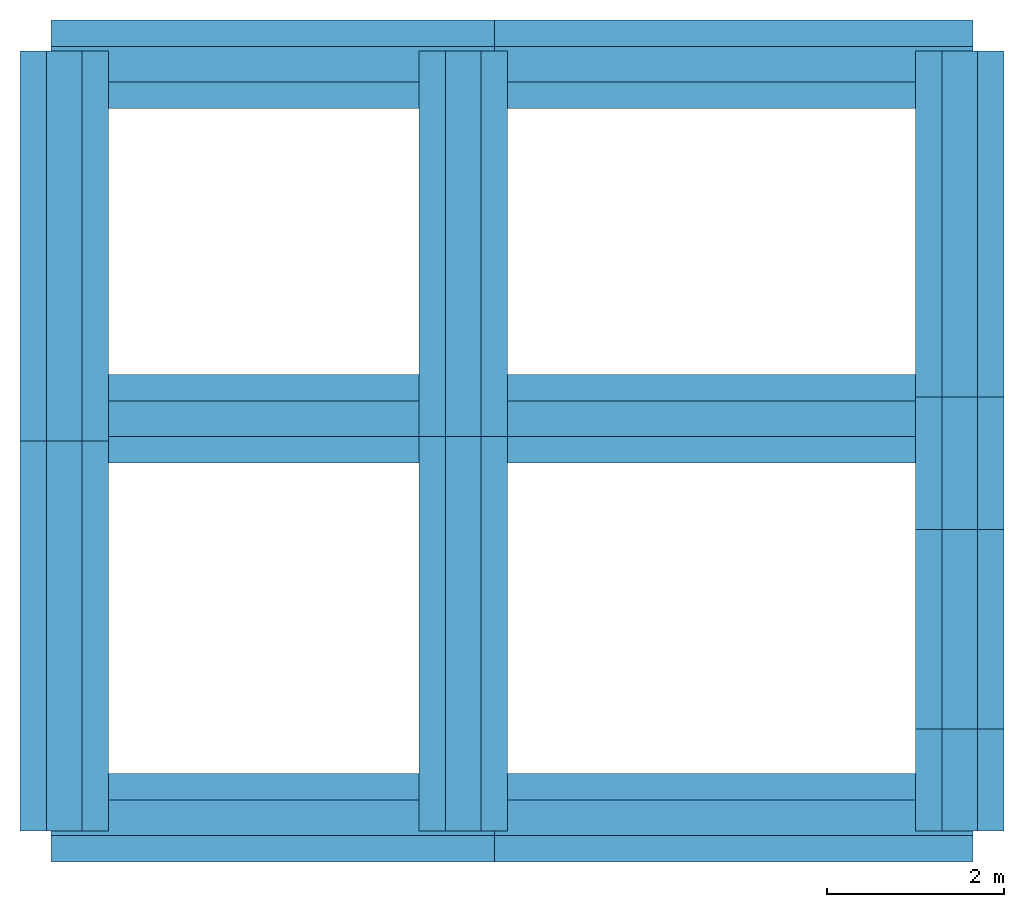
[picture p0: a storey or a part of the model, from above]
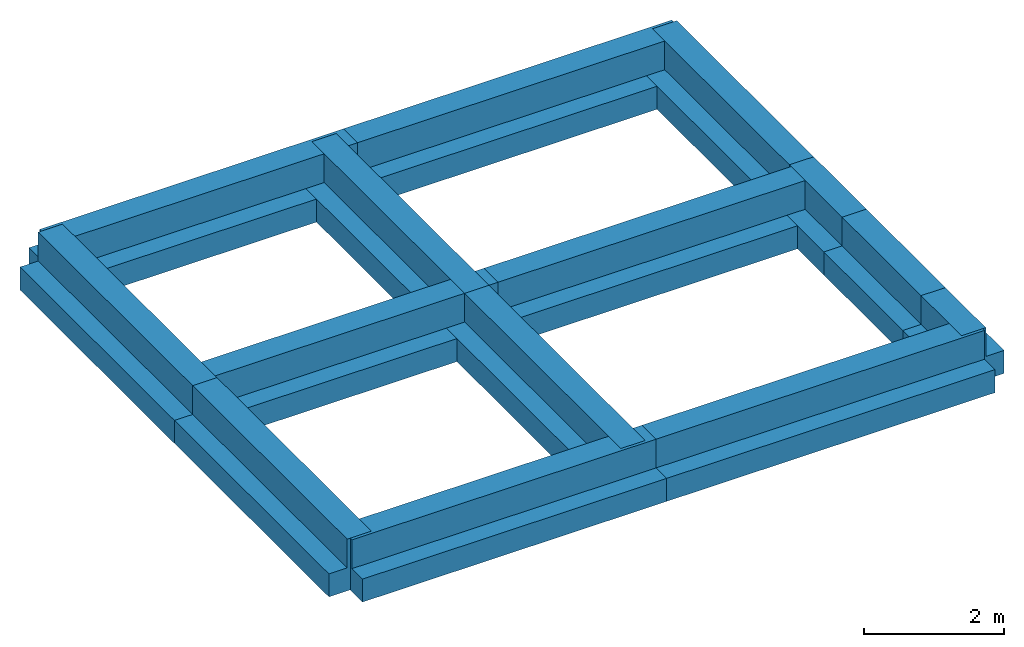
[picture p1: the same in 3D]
Properties of the parts of a building model (IFC2X3)

# File

# IfcSite, Default Site
RefElevation: 0 m

# IfcBuildingStorey (4)
In: Default Building
Name | Elevation (m)
Piano 2 | 6.4
Piano 1 | 3.2
Piano 3 | 1.3
Piano 0 | 0

# IfcBeam (57)
Material: C25/30
Name (Trave:...) | In
1 [Piano:0] | Piano 0
2 [Piano:0] | Piano 0
3 [Piano:0] | Piano 0
4 [Piano:0] | Piano 0
5 [Piano:0] | Piano 0
6 [Piano:0] | Piano 0
7 [Piano:0] | Piano 0
8 [Piano:0] | Piano 0
9 [Piano:0] | Piano 0
10 [Piano:0] | Piano 0
11 [Piano:0] | Piano 0
12 [Piano:0] | Piano 0
13 [Piano:0] | Piano 0
14 [Piano:0] | Piano 0
1 [Piano:3] | Piano 3
2 [Piano:3] | Piano 3
3 [Piano:3] | Piano 3
4 [Piano:3] | Piano 3
5 [Piano:3] | Piano 3
1 [Piano:1] | Piano 1
2 [Piano:1] | Piano 1
3 [Piano:1] | Piano 1
4 [Piano:1] | Piano 1
5 [Piano:1] | Piano 1
6 [Piano:1] | Piano 1
7 [Piano:1] | Piano 1
8 [Piano:1] | Piano 1
9 [Piano:1] | Piano 1
10 [Piano:1] | Piano 1
11 [Piano:1] | Piano 1
12 [Piano:1] | Piano 1
13 [Piano:1] | Piano 1
14 [Piano:1] | Piano 1
15 [Piano:1] | Piano 1
16 [Piano:1] | Piano 1
17 [Piano:1] | Piano 1
1 [Piano:2] | Piano 2
2 [Piano:2] | Piano 2
3 [Piano:2] | Piano 2
4 [Piano:2] | Piano 2
5 [Piano:2] | Piano 2
6 [Piano:2] | Piano 2
7 [Piano:2] | Piano 2
8 [Piano:2] | Piano 2
9 [Piano:2] | Piano 2
10 [Piano:2] | Piano 2
11 [Piano:2] | Piano 2
12 [Piano:2] | Piano 2
13 [Piano:2] | Piano 2
14 [Piano:2] | Piano 2
15 [Piano:2] | Piano 2
16 [Piano:2] | Piano 2
17 [Piano:2] | Piano 2
18 [Piano:2] | Piano 2
19 [Piano:2] | Piano 2
20 [Piano:2] | Piano 2
21 [Piano:2] | Piano 2

# IfcColumn (19)
Material: C25/30
Name (Pilastro:...) | In
11 [Piano:3] | Piano 3
1 [Piano:1] | Piano 1
2 [Piano:1] | Piano 1
3 [Piano:1] | Piano 1
4 [Piano:1] | Piano 1
5 [Piano:1] | Piano 1
6 [Piano:1] | Piano 1
7 [Piano:1] | Piano 1
8 [Piano:1] | Piano 1
9 [Piano:1] | Piano 1
1 [Piano:2] | Piano 2
2 [Piano:2] | Piano 2
3 [Piano:2] | Piano 2
4 [Piano:2] | Piano 2
5 [Piano:2] | Piano 2
6 [Piano:2] | Piano 2
7 [Piano:2] | Piano 2
8 [Piano:2] | Piano 2
9 [Piano:2] | Piano 2

# IfcSlab (29)
PredefinedType: FLOOR
Name | In
Balcone:2 [Piano:3] | Piano 3
Solaio:1 [Piano:1] | Piano 1
Solaio:2 [Piano:1] | Piano 1
Solaio:3 [Piano:1] | Piano 1
Solaio:4 [Piano:1] | Piano 1
Solaio:5 [Piano:1] | Piano 1
Solaio:6 [Piano:1] | Piano 1
Balcone:1 [Piano:1] | Piano 1
Balcone:2 [Piano:1] | Piano 1
Balcone:3 [Piano:1] | Piano 1
Balcone:4 [Piano:1] | Piano 1
Balcone:5 [Piano:1] | Piano 1
Balcone:6 [Piano:1] | Piano 1
Balcone:7 [Piano:1] | Piano 1
Solaio:1 [Piano:2] | Piano 2
Solaio:2 [Piano:2] | Piano 2
Solaio:3 [Piano:2] | Piano 2
Solaio:4 [Piano:2] | Piano 2
Solaio:5 [Piano:2] | Piano 2
Solaio:6 [Piano:2] | Piano 2
Solaio:7 [Piano:2] | Piano 2
Solaio:8 [Piano:2] | Piano 2
Solaio:9 [Piano:2] | Piano 2
Solaio:10 [Piano:2] | Piano 2
Balcone:1 [Piano:2] | Piano 2
Balcone:2 [Piano:2] | Piano 2
Balcone:3 [Piano:2] | Piano 2
Balcone:4 [Piano:2] | Piano 2
Balcone:5 [Piano:2] | Piano 2
